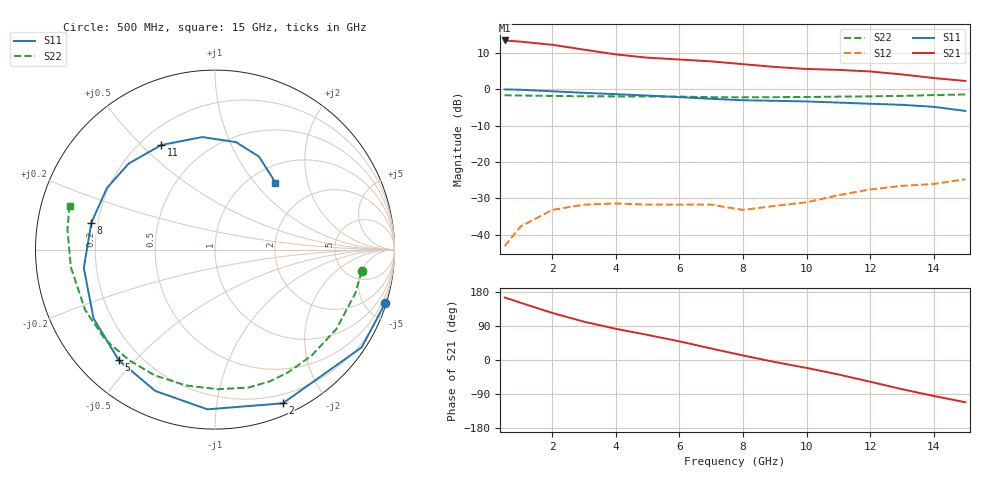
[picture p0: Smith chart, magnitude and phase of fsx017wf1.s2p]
! fsx017wf.s2p  1/99
! FSX017WF
! @8V-35mA
! 500MHZ 15GHZ 16
# GHZ S MA R 50
! S-parameter data
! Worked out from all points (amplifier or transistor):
!   16 points, 500 MHz to 15 GHz, reference 50 ohm
!   highest |S21| = 13.4 dB at 500 MHz (marker M1)
!   |S21| within 3 dB of that: start of sweep to 3.359 GHz
!   unconditionally stable (mu >= 1): 5.643 GHz to end of sweep
!   at 2 GHz: K = 0.27, MSG = 22.7 dB, |S12| = -33.2 dB
!   at 8 GHz: K = 1.96, MAG = 14.4 dB, |S12| = -33.2 dB
!   at 15 GHz: K = 1.35, MAG = 10.0 dB, |S12| = -24.7 dB
!   S11 on the Smith chart (normalised r, x): 500 MHz: 0.13, -6.49; 2 GHz: 0.11, -1.53; 5 GHz: 0.12, -0.45; 8 GHz: 0.17, +0.10; 11 GHz: 0.28, +0.57; 15 GHz: 1.29, +1.29
0.5  0.994 -17.5  4.666 165.0  0.007 75.3  0.826 -8.4
1  0.982 -33.7  4.499 151.2  0.013 69.9  0.819 -17.3
2  0.936 -66.2  4.066 124.2  0.022 47.3  0.808 -33.3
3  0.891 -92.7  3.486 101.1  0.026 30.2  0.799 -47.7
4  0.855 -112.9  3.001 82.3  0.027 17.5  0.796 -59.2
5  0.817 -131.0  2.706 66.1  0.026 7.6  0.795 -67.5
6  0.778 -150.4  2.555 49.2  0.026 0.0  0.791 -76.3
7  0.738 -172.0  2.407 30.3  0.026 -12.8  0.778 -88.8
8  0.705 167.8  2.206 12.0  0.022 -20.7  0.774 -102.1
9  0.693 150.3  2.02 -5.3  0.025 -24.2  0.777 -115.7
10  0.679 135.1  1.894 -20.9  0.028 -31.8  0.78 -127.6
11  0.655 117.2  1.842 -38.1  0.035 -43.3  0.791 -140.5
12  0.631 96.4  1.75 -57.3  0.042 -60.2  0.798 -155.2
13  0.61 78.9  1.595 -76.9  0.047 -79.6  0.809 -173.0
14  0.573 64.6  1.422 -94.9  0.05 -96.0  0.83 172.1
15  0.503 48.0  1.298 -111.5  0.058 -113.5  0.846 163.3
